##
## LEF for PtnCells ;
## created by Innovus v15.23-s045_1 on Sun Mar  1 18:37:18 2026
##

VERSION 5.8 ;

BUSBITCHARS "[]" ;
DIVIDERCHAR "/" ;

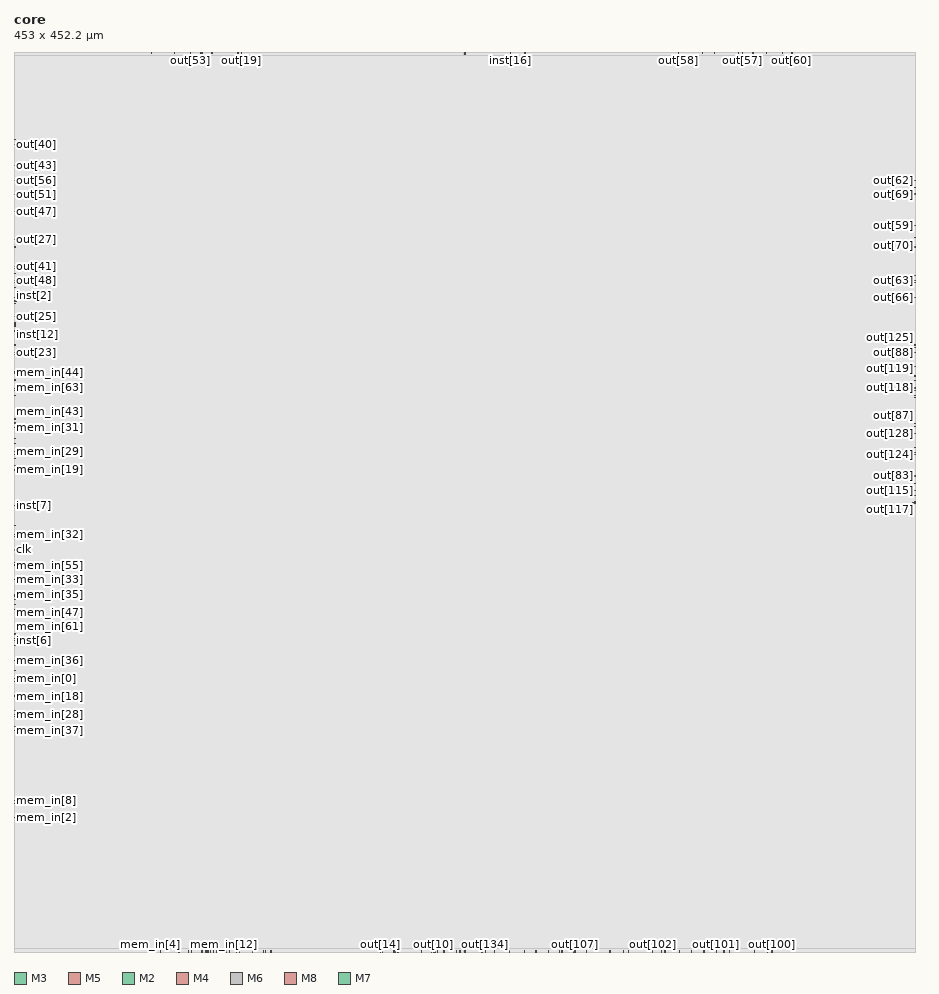
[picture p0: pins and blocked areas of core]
MACRO core
  CLASS BLOCK ;
  SIZE 453.0000 BY 452.2000 ;
  FOREIGN core 0.0000 0.0000 ;
  ORIGIN 0 0 ;
  SYMMETRY X Y R90 ;
  PIN clk
    DIRECTION INPUT ;
    USE SIGNAL ;
    PORT
      LAYER M3 ;
        RECT 0.0000 202.1500 0.5200 202.2500 ;
    END
  END clk
  PIN mem_in[63]
    DIRECTION INPUT ;
    USE SIGNAL ;
    PORT
      LAYER M3 ;
        RECT 0.0000 287.3500 0.5200 287.4500 ;
    END
  END mem_in[63]
  PIN mem_in[62]
    DIRECTION INPUT ;
    USE SIGNAL ;
    PORT
      LAYER M3 ;
        RECT 0.0000 249.9500 0.5200 250.0500 ;
    END
  END mem_in[62]
  PIN mem_in[61]
    DIRECTION INPUT ;
    USE SIGNAL ;
    PORT
      LAYER M3 ;
        RECT 0.0000 159.7500 0.5200 159.8500 ;
    END
  END mem_in[61]
  PIN mem_in[60]
    DIRECTION INPUT ;
    USE SIGNAL ;
    PORT
      LAYER M3 ;
        RECT 0.0000 195.5500 0.5200 195.6500 ;
    END
  END mem_in[60]
  PIN mem_in[59]
    DIRECTION INPUT ;
    USE SIGNAL ;
    PORT
      LAYER M3 ;
        RECT 0.0000 121.1500 0.5200 121.2500 ;
    END
  END mem_in[59]
  PIN mem_in[58]
    DIRECTION INPUT ;
    USE SIGNAL ;
    PORT
      LAYER M3 ;
        RECT 0.0000 141.3500 0.5200 141.4500 ;
    END
  END mem_in[58]
  PIN mem_in[57]
    DIRECTION INPUT ;
    USE SIGNAL ;
    PORT
      LAYER M3 ;
        RECT 0.0000 154.1500 0.5200 154.2500 ;
    END
  END mem_in[57]
  PIN mem_in[56]
    DIRECTION INPUT ;
    USE SIGNAL ;
    PORT
      LAYER M3 ;
        RECT 0.0000 244.3500 0.5200 244.4500 ;
    END
  END mem_in[56]
  PIN mem_in[55]
    DIRECTION INPUT ;
    USE SIGNAL ;
    PORT
      LAYER M3 ;
        RECT 0.0000 194.3500 0.5200 194.4500 ;
    END
  END mem_in[55]
  PIN mem_in[54]
    DIRECTION INPUT ;
    USE SIGNAL ;
    PORT
      LAYER M3 ;
        RECT 0.0000 113.1500 0.5200 113.2500 ;
    END
  END mem_in[54]
  PIN mem_in[53]
    DIRECTION INPUT ;
    USE SIGNAL ;
    PORT
      LAYER M3 ;
        RECT 0.0000 177.1500 0.5200 177.2500 ;
    END
  END mem_in[53]
  PIN mem_in[52]
    DIRECTION INPUT ;
    USE SIGNAL ;
    PORT
      LAYER M3 ;
        RECT 0.0000 178.5500 0.5200 178.6500 ;
    END
  END mem_in[52]
  PIN mem_in[51]
    DIRECTION INPUT ;
    USE SIGNAL ;
    PORT
      LAYER M3 ;
        RECT 0.0000 208.5500 0.5200 208.6500 ;
    END
  END mem_in[51]
  PIN mem_in[50]
    DIRECTION INPUT ;
    USE SIGNAL ;
    PORT
      LAYER M3 ;
        RECT 0.0000 255.5500 0.5200 255.6500 ;
    END
  END mem_in[50]
  PIN mem_in[49]
    DIRECTION INPUT ;
    USE SIGNAL ;
    PORT
      LAYER M3 ;
        RECT 0.0000 283.1500 0.5200 283.2500 ;
    END
  END mem_in[49]
  PIN mem_in[48]
    DIRECTION INPUT ;
    USE SIGNAL ;
    PORT
      LAYER M5 ;
        RECT 0.0000 201.9500 0.5200 202.0500 ;
    END
  END mem_in[48]
  PIN mem_in[47]
    DIRECTION INPUT ;
    USE SIGNAL ;
    PORT
      LAYER M3 ;
        RECT 0.0000 174.7500 0.5200 174.8500 ;
    END
  END mem_in[47]
  PIN mem_in[46]
    DIRECTION INPUT ;
    USE SIGNAL ;
    PORT
      LAYER M3 ;
        RECT 0.0000 214.3500 0.5200 214.4500 ;
    END
  END mem_in[46]
  PIN mem_in[45]
    DIRECTION INPUT ;
    USE SIGNAL ;
    PORT
      LAYER M3 ;
        RECT 0.0000 257.9500 0.5200 258.0500 ;
    END
  END mem_in[45]
  PIN mem_in[44]
    DIRECTION INPUT ;
    USE SIGNAL ;
    PORT
      LAYER M3 ;
        RECT 0.0000 291.3500 0.5200 291.4500 ;
    END
  END mem_in[44]
  PIN mem_in[43]
    DIRECTION INPUT ;
    USE SIGNAL ;
    PORT
      LAYER M3 ;
        RECT 0.0000 267.7500 0.5200 267.8500 ;
    END
  END mem_in[43]
  PIN mem_in[42]
    DIRECTION INPUT ;
    USE SIGNAL ;
    PORT
      LAYER M3 ;
        RECT 0.0000 171.9500 0.5200 172.0500 ;
    END
  END mem_in[42]
  PIN mem_in[41]
    DIRECTION INPUT ;
    USE SIGNAL ;
    PORT
      LAYER M3 ;
        RECT 0.0000 118.3500 0.5200 118.4500 ;
    END
  END mem_in[41]
  PIN mem_in[40]
    DIRECTION INPUT ;
    USE SIGNAL ;
    PORT
      LAYER M2 ;
        RECT 68.8500 0.0000 68.9500 0.5200 ;
    END
  END mem_in[40]
  PIN mem_in[39]
    DIRECTION INPUT ;
    USE SIGNAL ;
    PORT
      LAYER M2 ;
        RECT 125.2500 0.0000 125.3500 0.5200 ;
    END
  END mem_in[39]
  PIN mem_in[38]
    DIRECTION INPUT ;
    USE SIGNAL ;
    PORT
      LAYER M2 ;
        RECT 111.6500 0.0000 111.7500 0.5200 ;
    END
  END mem_in[38]
  PIN mem_in[37]
    DIRECTION INPUT ;
    USE SIGNAL ;
    PORT
      LAYER M3 ;
        RECT 0.0000 111.1500 0.5200 111.2500 ;
    END
  END mem_in[37]
  PIN mem_in[36]
    DIRECTION INPUT ;
    USE SIGNAL ;
    PORT
      LAYER M3 ;
        RECT 0.0000 146.3500 0.5200 146.4500 ;
    END
  END mem_in[36]
  PIN mem_in[35]
    DIRECTION INPUT ;
    USE SIGNAL ;
    PORT
      LAYER M3 ;
        RECT 0.0000 179.3500 0.5200 179.4500 ;
    END
  END mem_in[35]
  PIN mem_in[34]
    DIRECTION INPUT ;
    USE SIGNAL ;
    PORT
      LAYER M3 ;
        RECT 0.0000 265.7500 0.5200 265.8500 ;
    END
  END mem_in[34]
  PIN mem_in[33]
    DIRECTION INPUT ;
    USE SIGNAL ;
    PORT
      LAYER M3 ;
        RECT 0.0000 186.9500 0.5200 187.0500 ;
    END
  END mem_in[33]
  PIN mem_in[32]
    DIRECTION INPUT ;
    USE SIGNAL ;
    PORT
      LAYER M3 ;
        RECT 0.0000 209.5500 0.5200 209.6500 ;
    END
  END mem_in[32]
  PIN mem_in[31]
    DIRECTION INPUT ;
    USE SIGNAL ;
    PORT
      LAYER M3 ;
        RECT 0.0000 263.3500 0.5200 263.4500 ;
    END
  END mem_in[31]
  PIN mem_in[30]
    DIRECTION INPUT ;
    USE SIGNAL ;
    PORT
      LAYER M3 ;
        RECT 0.0000 157.5500 0.5200 157.6500 ;
    END
  END mem_in[30]
  PIN mem_in[29]
    DIRECTION INPUT ;
    USE SIGNAL ;
    PORT
      LAYER M3 ;
        RECT 0.0000 251.3500 0.5200 251.4500 ;
    END
  END mem_in[29]
  PIN mem_in[28]
    DIRECTION INPUT ;
    USE SIGNAL ;
    PORT
      LAYER M3 ;
        RECT 0.0000 119.1500 0.5200 119.2500 ;
    END
  END mem_in[28]
  PIN mem_in[27]
    DIRECTION INPUT ;
    USE SIGNAL ;
    PORT
      LAYER M2 ;
        RECT 119.6500 0.0000 119.7500 0.5200 ;
    END
  END mem_in[27]
  PIN mem_in[26]
    DIRECTION INPUT ;
    USE SIGNAL ;
    PORT
      LAYER M2 ;
        RECT 100.0500 0.0000 100.1500 0.5200 ;
    END
  END mem_in[26]
  PIN mem_in[25]
    DIRECTION INPUT ;
    USE SIGNAL ;
    PORT
      LAYER M2 ;
        RECT 126.2500 0.0000 126.3500 0.5200 ;
    END
  END mem_in[25]
  PIN mem_in[24]
    DIRECTION INPUT ;
    USE SIGNAL ;
    PORT
      LAYER M3 ;
        RECT 0.0000 74.5500 0.5200 74.6500 ;
    END
  END mem_in[24]
  PIN mem_in[23]
    DIRECTION INPUT ;
    USE SIGNAL ;
    PORT
      LAYER M2 ;
        RECT 97.4500 0.0000 97.5500 0.5200 ;
    END
  END mem_in[23]
  PIN mem_in[22]
    DIRECTION INPUT ;
    USE SIGNAL ;
    PORT
      LAYER M2 ;
        RECT 106.4500 0.0000 106.5500 0.5200 ;
    END
  END mem_in[22]
  PIN mem_in[21]
    DIRECTION INPUT ;
    USE SIGNAL ;
    PORT
      LAYER M2 ;
        RECT 82.8500 0.0000 82.9500 0.5200 ;
    END
  END mem_in[21]
  PIN mem_in[20]
    DIRECTION INPUT ;
    USE SIGNAL ;
    PORT
      LAYER M2 ;
        RECT 113.2500 0.0000 113.3500 0.5200 ;
    END
  END mem_in[20]
  PIN mem_in[19]
    DIRECTION INPUT ;
    USE SIGNAL ;
    PORT
      LAYER M3 ;
        RECT 0.0000 242.1500 0.5200 242.2500 ;
    END
  END mem_in[19]
  PIN mem_in[18]
    DIRECTION INPUT ;
    USE SIGNAL ;
    PORT
      LAYER M3 ;
        RECT 0.0000 128.5500 0.5200 128.6500 ;
    END
  END mem_in[18]
  PIN mem_in[17]
    DIRECTION INPUT ;
    USE SIGNAL ;
    PORT
      LAYER M2 ;
        RECT 98.8500 0.0000 98.9500 0.5200 ;
    END
  END mem_in[17]
  PIN mem_in[16]
    DIRECTION INPUT ;
    USE SIGNAL ;
    PORT
      LAYER M2 ;
        RECT 108.0500 0.0000 108.1500 0.5200 ;
    END
  END mem_in[16]
  PIN mem_in[15]
    DIRECTION INPUT ;
    USE SIGNAL ;
    PORT
      LAYER M2 ;
        RECT 73.4500 0.0000 73.5500 0.5200 ;
    END
  END mem_in[15]
  PIN mem_in[14]
    DIRECTION INPUT ;
    USE SIGNAL ;
    PORT
      LAYER M2 ;
        RECT 101.8500 0.0000 101.9500 0.5200 ;
    END
  END mem_in[14]
  PIN mem_in[13]
    DIRECTION INPUT ;
    USE SIGNAL ;
    PORT
      LAYER M2 ;
        RECT 104.6500 0.0000 104.7500 0.5200 ;
    END
  END mem_in[13]
  PIN mem_in[12]
    DIRECTION INPUT ;
    USE SIGNAL ;
    PORT
      LAYER M2 ;
        RECT 105.2500 0.0000 105.3500 0.5200 ;
    END
  END mem_in[12]
  PIN mem_in[11]
    DIRECTION INPUT ;
    USE SIGNAL ;
    PORT
      LAYER M3 ;
        RECT 0.0000 247.9500 0.5200 248.0500 ;
    END
  END mem_in[11]
  PIN mem_in[10]
    DIRECTION INPUT ;
    USE SIGNAL ;
    PORT
      LAYER M3 ;
        RECT 0.0000 135.7500 0.5200 135.8500 ;
    END
  END mem_in[10]
  PIN mem_in[9]
    DIRECTION INPUT ;
    USE SIGNAL ;
    PORT
      LAYER M2 ;
        RECT 129.0500 0.0000 129.1500 0.5200 ;
    END
  END mem_in[9]
  PIN mem_in[8]
    DIRECTION INPUT ;
    USE SIGNAL ;
    PORT
      LAYER M3 ;
        RECT 0.0000 75.9500 0.5200 76.0500 ;
    END
  END mem_in[8]
  PIN mem_in[7]
    DIRECTION INPUT ;
    USE SIGNAL ;
    PORT
      LAYER M2 ;
        RECT 96.4500 0.0000 96.5500 0.5200 ;
    END
  END mem_in[7]
  PIN mem_in[6]
    DIRECTION INPUT ;
    USE SIGNAL ;
    PORT
      LAYER M2 ;
        RECT 87.6500 0.0000 87.7500 0.5200 ;
    END
  END mem_in[6]
  PIN mem_in[5]
    DIRECTION INPUT ;
    USE SIGNAL ;
    PORT
      LAYER M2 ;
        RECT 89.0500 0.0000 89.1500 0.5200 ;
    END
  END mem_in[5]
  PIN mem_in[4]
    DIRECTION INPUT ;
    USE SIGNAL ;
    PORT
      LAYER M2 ;
        RECT 68.4500 0.0000 68.5500 0.5200 ;
    END
  END mem_in[4]
  PIN mem_in[3]
    DIRECTION INPUT ;
    USE SIGNAL ;
    PORT
      LAYER M2 ;
        RECT 94.4500 0.0000 94.5500 0.5200 ;
    END
  END mem_in[3]
  PIN mem_in[2]
    DIRECTION INPUT ;
    USE SIGNAL ;
    PORT
      LAYER M3 ;
        RECT 0.0000 67.3500 0.5200 67.4500 ;
    END
  END mem_in[2]
  PIN mem_in[1]
    DIRECTION INPUT ;
    USE SIGNAL ;
    PORT
      LAYER M4 ;
        RECT 68.8500 0.0000 68.9500 0.5200 ;
    END
  END mem_in[1]
  PIN mem_in[0]
    DIRECTION INPUT ;
    USE SIGNAL ;
    PORT
      LAYER M3 ;
        RECT 0.0000 137.5500 0.5200 137.6500 ;
    END
  END mem_in[0]
  PIN inst[18]
    DIRECTION INPUT ;
    USE SIGNAL ;
    PORT
      LAYER M2 ;
        RECT 226.4500 451.6800 226.5500 452.2000 ;
    END
  END inst[18]
  PIN inst[17]
    DIRECTION INPUT ;
    USE SIGNAL ;
    PORT
      LAYER M4 ;
        RECT 226.4500 451.6800 226.5500 452.2000 ;
    END
  END inst[17]
  PIN inst[16]
    DIRECTION INPUT ;
    USE SIGNAL ;
    PORT
      LAYER M2 ;
        RECT 249.2500 451.6800 249.3500 452.2000 ;
    END
  END inst[16]
  PIN inst[15]
    DIRECTION INPUT ;
    USE SIGNAL ;
    PORT
      LAYER M3 ;
        RECT 0.0000 316.1500 0.5200 316.2500 ;
    END
  END inst[15]
  PIN inst[14]
    DIRECTION INPUT ;
    USE SIGNAL ;
    PORT
      LAYER M3 ;
        RECT 0.0000 314.9500 0.5200 315.0500 ;
    END
  END inst[14]
  PIN inst[13]
    DIRECTION INPUT ;
    USE SIGNAL ;
    PORT
      LAYER M3 ;
        RECT 0.0000 311.9500 0.5200 312.0500 ;
    END
  END inst[13]
  PIN inst[12]
    DIRECTION INPUT ;
    USE SIGNAL ;
    PORT
      LAYER M3 ;
        RECT 0.0000 314.1500 0.5200 314.2500 ;
    END
  END inst[12]
  PIN inst[11]
    DIRECTION INPUT ;
    USE SIGNAL ;
    PORT
      LAYER M6 ;
        RECT 226.4500 451.6800 226.5500 452.2000 ;
    END
  END inst[11]
  PIN inst[10]
    DIRECTION INPUT ;
    USE SIGNAL ;
    PORT
      LAYER M8 ;
        RECT 226.3000 450.7850 226.7000 452.2000 ;
    END
  END inst[10]
  PIN inst[9]
    DIRECTION INPUT ;
    USE SIGNAL ;
    PORT
      LAYER M2 ;
        RECT 226.4500 0.0000 226.5500 0.5200 ;
    END
  END inst[9]
  PIN inst[8]
    DIRECTION INPUT ;
    USE SIGNAL ;
    PORT
      LAYER M4 ;
        RECT 226.4500 0.0000 226.5500 0.5200 ;
    END
  END inst[8]
  PIN inst[7]
    DIRECTION INPUT ;
    USE SIGNAL ;
    PORT
      LAYER M3 ;
        RECT 0.0000 224.1500 0.5200 224.2500 ;
    END
  END inst[7]
  PIN inst[6]
    DIRECTION INPUT ;
    USE SIGNAL ;
    PORT
      LAYER M3 ;
        RECT 0.0000 156.3500 0.5200 156.4500 ;
    END
  END inst[6]
  PIN inst[5]
    DIRECTION INPUT ;
    USE SIGNAL ;
    PORT
      LAYER M3 ;
        RECT 0.0000 326.9500 0.5200 327.0500 ;
    END
  END inst[5]
  PIN inst[4]
    DIRECTION INPUT ;
    USE SIGNAL ;
    PORT
      LAYER M5 ;
        RECT 0.0000 326.9500 0.5200 327.0500 ;
    END
  END inst[4]
  PIN inst[3]
    DIRECTION INPUT ;
    USE SIGNAL ;
    PORT
      LAYER M7 ;
        RECT 0.0000 327.0000 1.4150 327.4000 ;
    END
  END inst[3]
  PIN inst[2]
    DIRECTION INPUT ;
    USE SIGNAL ;
    PORT
      LAYER M3 ;
        RECT 0.0000 325.9500 0.5200 326.0500 ;
    END
  END inst[2]
  PIN inst[1]
    DIRECTION INPUT ;
    USE SIGNAL ;
    PORT
      LAYER M6 ;
        RECT 226.4500 0.0000 226.5500 0.5200 ;
    END
  END inst[1]
  PIN inst[0]
    DIRECTION INPUT ;
    USE SIGNAL ;
    PORT
      LAYER M8 ;
        RECT 226.3000 0.0000 226.7000 1.4150 ;
    END
  END inst[0]
  PIN reset
    DIRECTION INPUT ;
    USE SIGNAL ;
    PORT
      LAYER M2 ;
        RECT 256.6500 451.6800 256.7500 452.2000 ;
    END
  END reset
  PIN out[151]
    DIRECTION OUTPUT ;
    USE SIGNAL ;
    PORT
      LAYER M2 ;
        RECT 256.4500 0.0000 256.5500 0.5200 ;
    END
  END out[151]
  PIN out[150]
    DIRECTION OUTPUT ;
    USE SIGNAL ;
    PORT
      LAYER M2 ;
        RECT 235.0500 0.0000 235.1500 0.5200 ;
    END
  END out[150]
  PIN out[149]
    DIRECTION OUTPUT ;
    USE SIGNAL ;
    PORT
      LAYER M2 ;
        RECT 274.0500 0.0000 274.1500 0.5200 ;
    END
  END out[149]
  PIN out[148]
    DIRECTION OUTPUT ;
    USE SIGNAL ;
    PORT
      LAYER M2 ;
        RECT 299.4500 0.0000 299.5500 0.5200 ;
    END
  END out[148]
  PIN out[147]
    DIRECTION OUTPUT ;
    USE SIGNAL ;
    PORT
      LAYER M2 ;
        RECT 287.4500 0.0000 287.5500 0.5200 ;
    END
  END out[147]
  PIN out[146]
    DIRECTION OUTPUT ;
    USE SIGNAL ;
    PORT
      LAYER M2 ;
        RECT 262.4500 0.0000 262.5500 0.5200 ;
    END
  END out[146]
  PIN out[145]
    DIRECTION OUTPUT ;
    USE SIGNAL ;
    PORT
      LAYER M2 ;
        RECT 281.8500 0.0000 281.9500 0.5200 ;
    END
  END out[145]
  PIN out[144]
    DIRECTION OUTPUT ;
    USE SIGNAL ;
    PORT
      LAYER M2 ;
        RECT 275.2500 0.0000 275.3500 0.5200 ;
    END
  END out[144]
  PIN out[143]
    DIRECTION OUTPUT ;
    USE SIGNAL ;
    PORT
      LAYER M2 ;
        RECT 236.8500 0.0000 236.9500 0.5200 ;
    END
  END out[143]
  PIN out[142]
    DIRECTION OUTPUT ;
    USE SIGNAL ;
    PORT
      LAYER M2 ;
        RECT 261.8500 0.0000 261.9500 0.5200 ;
    END
  END out[142]
  PIN out[141]
    DIRECTION OUTPUT ;
    USE SIGNAL ;
    PORT
      LAYER M2 ;
        RECT 241.4500 0.0000 241.5500 0.5200 ;
    END
  END out[141]
  PIN out[140]
    DIRECTION OUTPUT ;
    USE SIGNAL ;
    PORT
      LAYER M4 ;
        RECT 236.8500 0.0000 236.9500 0.5200 ;
    END
  END out[140]
  PIN out[139]
    DIRECTION OUTPUT ;
    USE SIGNAL ;
    PORT
      LAYER M4 ;
        RECT 262.0500 0.0000 262.1500 0.5200 ;
    END
  END out[139]
  PIN out[138]
    DIRECTION OUTPUT ;
    USE SIGNAL ;
    PORT
      LAYER M2 ;
        RECT 248.8500 0.0000 248.9500 0.5200 ;
    END
  END out[138]
  PIN out[137]
    DIRECTION OUTPUT ;
    USE SIGNAL ;
    PORT
      LAYER M4 ;
        RECT 256.4500 0.0000 256.5500 0.5200 ;
    END
  END out[137]
  PIN out[136]
    DIRECTION OUTPUT ;
    USE SIGNAL ;
    PORT
      LAYER M4 ;
        RECT 262.4500 0.0000 262.5500 0.5200 ;
    END
  END out[136]
  PIN out[135]
    DIRECTION OUTPUT ;
    USE SIGNAL ;
    PORT
      LAYER M4 ;
        RECT 299.4500 0.0000 299.5500 0.5200 ;
    END
  END out[135]
  PIN out[134]
    DIRECTION OUTPUT ;
    USE SIGNAL ;
    PORT
      LAYER M6 ;
        RECT 236.8500 0.0000 236.9500 0.5200 ;
    END
  END out[134]
  PIN out[133]
    DIRECTION OUTPUT ;
    USE SIGNAL ;
    PORT
      LAYER M2 ;
        RECT 268.6500 0.0000 268.7500 0.5200 ;
    END
  END out[133]
  PIN out[132]
    DIRECTION OUTPUT ;
    USE SIGNAL ;
    PORT
      LAYER M3 ;
        RECT 452.4800 250.9500 453.0000 251.0500 ;
    END
  END out[132]
  PIN out[131]
    DIRECTION OUTPUT ;
    USE SIGNAL ;
    PORT
      LAYER M3 ;
        RECT 452.4800 225.7500 453.0000 225.8500 ;
    END
  END out[131]
  PIN out[130]
    DIRECTION OUTPUT ;
    USE SIGNAL ;
    PORT
      LAYER M5 ;
        RECT 452.4800 225.7500 453.0000 225.8500 ;
    END
  END out[130]
  PIN out[129]
    DIRECTION OUTPUT ;
    USE SIGNAL ;
    PORT
      LAYER M3 ;
        RECT 452.4800 229.3500 453.0000 229.4500 ;
    END
  END out[129]
  PIN out[128]
    DIRECTION OUTPUT ;
    USE SIGNAL ;
    PORT
      LAYER M3 ;
        RECT 452.4800 260.5500 453.0000 260.6500 ;
    END
  END out[128]
  PIN out[127]
    DIRECTION OUTPUT ;
    USE SIGNAL ;
    PORT
      LAYER M7 ;
        RECT 451.5850 225.4000 453.0000 225.8000 ;
    END
  END out[127]
  PIN out[126]
    DIRECTION OUTPUT ;
    USE SIGNAL ;
    PORT
      LAYER M3 ;
        RECT 452.4800 264.1500 453.0000 264.2500 ;
    END
  END out[126]
  PIN out[125]
    DIRECTION OUTPUT ;
    USE SIGNAL ;
    PORT
      LAYER M3 ;
        RECT 452.4800 304.9500 453.0000 305.0500 ;
    END
  END out[125]
  PIN out[124]
    DIRECTION OUTPUT ;
    USE SIGNAL ;
    PORT
      LAYER M3 ;
        RECT 452.4800 249.7500 453.0000 249.8500 ;
    END
  END out[124]
  PIN out[123]
    DIRECTION OUTPUT ;
    USE SIGNAL ;
    PORT
      LAYER M3 ;
        RECT 452.4800 294.1500 453.0000 294.2500 ;
    END
  END out[123]
  PIN out[122]
    DIRECTION OUTPUT ;
    USE SIGNAL ;
    PORT
      LAYER M3 ;
        RECT 452.4800 282.1500 453.0000 282.2500 ;
    END
  END out[122]
  PIN out[121]
    DIRECTION OUTPUT ;
    USE SIGNAL ;
    PORT
      LAYER M5 ;
        RECT 452.4800 282.1500 453.0000 282.2500 ;
    END
  END out[121]
  PIN out[120]
    DIRECTION OUTPUT ;
    USE SIGNAL ;
    PORT
      LAYER M3 ;
        RECT 452.4800 225.3500 453.0000 225.4500 ;
    END
  END out[120]
  PIN out[119]
    DIRECTION OUTPUT ;
    USE SIGNAL ;
    PORT
      LAYER M3 ;
        RECT 452.4800 289.3500 453.0000 289.4500 ;
    END
  END out[119]
  PIN out[118]
    DIRECTION OUTPUT ;
    USE SIGNAL ;
    PORT
      LAYER M3 ;
        RECT 452.4800 283.3500 453.0000 283.4500 ;
    END
  END out[118]
  PIN out[117]
    DIRECTION OUTPUT ;
    USE SIGNAL ;
    PORT
      LAYER M3 ;
        RECT 452.4800 226.1500 453.0000 226.2500 ;
    END
  END out[117]
  PIN out[116]
    DIRECTION OUTPUT ;
    USE SIGNAL ;
    PORT
      LAYER M5 ;
        RECT 452.4800 229.3500 453.0000 229.4500 ;
    END
  END out[116]
  PIN out[115]
    DIRECTION OUTPUT ;
    USE SIGNAL ;
    PORT
      LAYER M3 ;
        RECT 452.4800 231.7500 453.0000 231.8500 ;
    END
  END out[115]
  PIN out[114]
    DIRECTION OUTPUT ;
    USE SIGNAL ;
    PORT
      LAYER M3 ;
        RECT 452.4800 303.7500 453.0000 303.8500 ;
    END
  END out[114]
  PIN out[113]
    DIRECTION OUTPUT ;
    USE SIGNAL ;
    PORT
      LAYER M2 ;
        RECT 378.4500 0.0000 378.5500 0.5200 ;
    END
  END out[113]
  PIN out[112]
    DIRECTION OUTPUT ;
    USE SIGNAL ;
    PORT
      LAYER M2 ;
        RECT 325.4500 0.0000 325.5500 0.5200 ;
    END
  END out[112]
  PIN out[111]
    DIRECTION OUTPUT ;
    USE SIGNAL ;
    PORT
      LAYER M2 ;
        RECT 306.0500 0.0000 306.1500 0.5200 ;
    END
  END out[111]
  PIN out[110]
    DIRECTION OUTPUT ;
    USE SIGNAL ;
    PORT
      LAYER M2 ;
        RECT 327.0500 0.0000 327.1500 0.5200 ;
    END
  END out[110]
  PIN out[109]
    DIRECTION OUTPUT ;
    USE SIGNAL ;
    PORT
      LAYER M2 ;
        RECT 340.4500 0.0000 340.5500 0.5200 ;
    END
  END out[109]
  PIN out[108]
    DIRECTION OUTPUT ;
    USE SIGNAL ;
    PORT
      LAYER M6 ;
        RECT 299.4500 0.0000 299.5500 0.5200 ;
    END
  END out[108]
  PIN out[107]
    DIRECTION OUTPUT ;
    USE SIGNAL ;
    PORT
      LAYER M4 ;
        RECT 281.8500 0.0000 281.9500 0.5200 ;
    END
  END out[107]
  PIN out[106]
    DIRECTION OUTPUT ;
    USE SIGNAL ;
    PORT
      LAYER M2 ;
        RECT 359.4500 0.0000 359.5500 0.5200 ;
    END
  END out[106]
  PIN out[105]
    DIRECTION OUTPUT ;
    USE SIGNAL ;
    PORT
      LAYER M2 ;
        RECT 281.2500 0.0000 281.3500 0.5200 ;
    END
  END out[105]
  PIN out[104]
    DIRECTION OUTPUT ;
    USE SIGNAL ;
    PORT
      LAYER M4 ;
        RECT 327.2500 0.0000 327.3500 0.5200 ;
    END
  END out[104]
  PIN out[103]
    DIRECTION OUTPUT ;
    USE SIGNAL ;
    PORT
      LAYER M2 ;
        RECT 356.6500 0.0000 356.7500 0.5200 ;
    END
  END out[103]
  PIN out[102]
    DIRECTION OUTPUT ;
    USE SIGNAL ;
    PORT
      LAYER M2 ;
        RECT 320.8500 0.0000 320.9500 0.5200 ;
    END
  END out[102]
  PIN out[101]
    DIRECTION OUTPUT ;
    USE SIGNAL ;
    PORT
      LAYER M2 ;
        RECT 352.8500 0.0000 352.9500 0.5200 ;
    END
  END out[101]
  PIN out[100]
    DIRECTION OUTPUT ;
    USE SIGNAL ;
    PORT
      LAYER M2 ;
        RECT 380.8500 0.0000 380.9500 0.5200 ;
    END
  END out[100]
  PIN out[99]
    DIRECTION OUTPUT ;
    USE SIGNAL ;
    PORT
      LAYER M2 ;
        RECT 372.0500 0.0000 372.1500 0.5200 ;
    END
  END out[99]
  PIN out[98]
    DIRECTION OUTPUT ;
    USE SIGNAL ;
    PORT
      LAYER M4 ;
        RECT 306.0500 0.0000 306.1500 0.5200 ;
    END
  END out[98]
  PIN out[97]
    DIRECTION OUTPUT ;
    USE SIGNAL ;
    PORT
      LAYER M2 ;
        RECT 334.2500 0.0000 334.3500 0.5200 ;
    END
  END out[97]
  PIN out[96]
    DIRECTION OUTPUT ;
    USE SIGNAL ;
    PORT
      LAYER M2 ;
        RECT 308.8500 0.0000 308.9500 0.5200 ;
    END
  END out[96]
  PIN out[95]
    DIRECTION OUTPUT ;
    USE SIGNAL ;
    PORT
      LAYER M2 ;
        RECT 346.6500 0.0000 346.7500 0.5200 ;
    END
  END out[95]
  PIN out[94]
    DIRECTION OUTPUT ;
    USE SIGNAL ;
    PORT
      LAYER M3 ;
        RECT 452.4800 339.7500 453.0000 339.8500 ;
    END
  END out[94]
  PIN out[93]
    DIRECTION OUTPUT ;
    USE SIGNAL ;
    PORT
      LAYER M3 ;
        RECT 452.4800 238.9500 453.0000 239.0500 ;
    END
  END out[93]
  PIN out[92]
    DIRECTION OUTPUT ;
    USE SIGNAL ;
    PORT
      LAYER M3 ;
        RECT 452.4800 354.1500 453.0000 354.2500 ;
    END
  END out[92]
  PIN out[91]
    DIRECTION OUTPUT ;
    USE SIGNAL ;
    PORT
      LAYER M3 ;
        RECT 452.4800 278.5500 453.0000 278.6500 ;
    END
  END out[91]
  PIN out[90]
    DIRECTION OUTPUT ;
    USE SIGNAL ;
    PORT
      LAYER M3 ;
        RECT 452.4800 279.7500 453.0000 279.8500 ;
    END
  END out[90]
  PIN out[89]
    DIRECTION OUTPUT ;
    USE SIGNAL ;
    PORT
      LAYER M3 ;
        RECT 452.4800 301.3500 453.0000 301.4500 ;
    END
  END out[89]
  PIN out[88]
    DIRECTION OUTPUT ;
    USE SIGNAL ;
    PORT
      LAYER M5 ;
        RECT 452.4800 301.3500 453.0000 301.4500 ;
    END
  END out[88]
  PIN out[87]
    DIRECTION OUTPUT ;
    USE SIGNAL ;
    PORT
      LAYER M3 ;
        RECT 452.4800 265.3500 453.0000 265.4500 ;
    END
  END out[87]
  PIN out[86]
    DIRECTION OUTPUT ;
    USE SIGNAL ;
    PORT
      LAYER M5 ;
        RECT 452.4800 279.7500 453.0000 279.8500 ;
    END
  END out[86]
  PIN out[85]
    DIRECTION OUTPUT ;
    USE SIGNAL ;
    PORT
      LAYER M3 ;
        RECT 452.4800 286.9500 453.0000 287.0500 ;
    END
  END out[85]
  PIN out[84]
    DIRECTION OUTPUT ;
    USE SIGNAL ;
    PORT
      LAYER M3 ;
        RECT 452.4800 337.3500 453.0000 337.4500 ;
    END
  END out[84]
  PIN out[83]
    DIRECTION OUTPUT ;
    USE SIGNAL ;
    PORT
      LAYER M3 ;
        RECT 452.4800 235.3500 453.0000 235.4500 ;
    END
  END out[83]
  PIN out[82]
    DIRECTION OUTPUT ;
    USE SIGNAL ;
    PORT
      LAYER M5 ;
        RECT 452.4800 238.9500 453.0000 239.0500 ;
    END
  END out[82]
  PIN out[81]
    DIRECTION OUTPUT ;
    USE SIGNAL ;
    PORT
      LAYER M5 ;
        RECT 452.4800 289.3500 453.0000 289.4500 ;
    END
  END out[81]
  PIN out[80]
    DIRECTION OUTPUT ;
    USE SIGNAL ;
    PORT
      LAYER M3 ;
        RECT 452.4800 336.1500 453.0000 336.2500 ;
    END
  END out[80]
  PIN out[79]
    DIRECTION OUTPUT ;
    USE SIGNAL ;
    PORT
      LAYER M7 ;
        RECT 451.5850 239.0000 453.0000 239.4000 ;
    END
  END out[79]
  PIN out[78]
    DIRECTION OUTPUT ;
    USE SIGNAL ;
    PORT
      LAYER M5 ;
        RECT 452.4800 286.9500 453.0000 287.0500 ;
    END
  END out[78]
  PIN out[77]
    DIRECTION OUTPUT ;
    USE SIGNAL ;
    PORT
      LAYER M3 ;
        RECT 452.4800 253.3500 453.0000 253.4500 ;
    END
  END out[77]
  PIN out[76]
    DIRECTION OUTPUT ;
    USE SIGNAL ;
    PORT
      LAYER M3 ;
        RECT 452.4800 328.9500 453.0000 329.0500 ;
    END
  END out[76]
  PIN out[75]
    DIRECTION OUTPUT ;
    USE SIGNAL ;
    PORT
      LAYER M2 ;
        RECT 363.8500 451.6800 363.9500 452.2000 ;
    END
  END out[75]
  PIN out[74]
    DIRECTION OUTPUT ;
    USE SIGNAL ;
    PORT
      LAYER M3 ;
        RECT 452.4800 384.1500 453.0000 384.2500 ;
    END
  END out[74]
  PIN out[73]
    DIRECTION OUTPUT ;
    USE SIGNAL ;
    PORT
      LAYER M3 ;
        RECT 452.4800 380.5500 453.0000 380.6500 ;
    END
  END out[73]
  PIN out[72]
    DIRECTION OUTPUT ;
    USE SIGNAL ;
    PORT
      LAYER M2 ;
        RECT 371.2500 451.6800 371.3500 452.2000 ;
    END
  END out[72]
  PIN out[71]
    DIRECTION OUTPUT ;
    USE SIGNAL ;
    PORT
      LAYER M2 ;
        RECT 352.0500 451.6800 352.1500 452.2000 ;
    END
  END out[71]
  PIN out[70]
    DIRECTION OUTPUT ;
    USE SIGNAL ;
    PORT
      LAYER M3 ;
        RECT 452.4800 358.9500 453.0000 359.0500 ;
    END
  END out[70]
  PIN out[69]
    DIRECTION OUTPUT ;
    USE SIGNAL ;
    PORT
      LAYER M5 ;
        RECT 452.4800 380.5500 453.0000 380.6500 ;
    END
  END out[69]
  PIN out[68]
    DIRECTION OUTPUT ;
    USE SIGNAL ;
    PORT
      LAYER M2 ;
        RECT 346.0500 451.6800 346.1500 452.2000 ;
    END
  END out[68]
  PIN out[67]
    DIRECTION OUTPUT ;
    USE SIGNAL ;
    PORT
      LAYER M2 ;
        RECT 386.0500 451.6800 386.1500 452.2000 ;
    END
  END out[67]
  PIN out[66]
    DIRECTION OUTPUT ;
    USE SIGNAL ;
    PORT
      LAYER M5 ;
        RECT 452.4800 328.9500 453.0000 329.0500 ;
    END
  END out[66]
  PIN out[65]
    DIRECTION OUTPUT ;
    USE SIGNAL ;
    PORT
      LAYER M7 ;
        RECT 451.5850 328.6000 453.0000 329.0000 ;
    END
  END out[65]
  PIN out[64]
    DIRECTION OUTPUT ;
    USE SIGNAL ;
    PORT
      LAYER M7 ;
        RECT 451.5850 380.6000 453.0000 381.0000 ;
    END
  END out[64]
  PIN out[63]
    DIRECTION OUTPUT ;
    USE SIGNAL ;
    PORT
      LAYER M5 ;
        RECT 452.4800 337.3500 453.0000 337.4500 ;
    END
  END out[63]
  PIN out[62]
    DIRECTION OUTPUT ;
    USE SIGNAL ;
    PORT
      LAYER M3 ;
        RECT 452.4800 387.7500 453.0000 387.8500 ;
    END
  END out[62]
  PIN out[61]
    DIRECTION OUTPUT ;
    USE SIGNAL ;
    PORT
      LAYER M2 ;
        RECT 377.8500 451.6800 377.9500 452.2000 ;
    END
  END out[61]
  PIN out[60]
    DIRECTION OUTPUT ;
    USE SIGNAL ;
    PORT
      LAYER M2 ;
        RECT 390.8500 451.6800 390.9500 452.2000 ;
    END
  END out[60]
  PIN out[59]
    DIRECTION OUTPUT ;
    USE SIGNAL ;
    PORT
      LAYER M3 ;
        RECT 452.4800 364.9500 453.0000 365.0500 ;
    END
  END out[59]
  PIN out[58]
    DIRECTION OUTPUT ;
    USE SIGNAL ;
    PORT
      LAYER M2 ;
        RECT 333.6500 451.6800 333.7500 452.2000 ;
    END
  END out[58]
  PIN out[57]
    DIRECTION OUTPUT ;
    USE SIGNAL ;
    PORT
      LAYER M2 ;
        RECT 365.8500 451.6800 365.9500 452.2000 ;
    END
  END out[57]
  PIN out[56]
    DIRECTION OUTPUT ;
    USE SIGNAL ;
    PORT
      LAYER M3 ;
        RECT 0.0000 387.7500 0.5200 387.8500 ;
    END
  END out[56]
  PIN out[55]
    DIRECTION OUTPUT ;
    USE SIGNAL ;
    PORT
      LAYER M2 ;
        RECT 94.4500 451.6800 94.5500 452.2000 ;
    END
  END out[55]
  PIN out[54]
    DIRECTION OUTPUT ;
    USE SIGNAL ;
    PORT
      LAYER M2 ;
        RECT 80.6500 451.6800 80.7500 452.2000 ;
    END
  END out[54]
  PIN out[53]
    DIRECTION OUTPUT ;
    USE SIGNAL ;
    PORT
      LAYER M2 ;
        RECT 88.4500 451.6800 88.5500 452.2000 ;
    END
  END out[53]
  PIN out[52]
    DIRECTION OUTPUT ;
    USE SIGNAL ;
    PORT
      LAYER M3 ;
        RECT 0.0000 340.9500 0.5200 341.0500 ;
    END
  END out[52]
  PIN out[51]
    DIRECTION OUTPUT ;
    USE SIGNAL ;
    PORT
      LAYER M3 ;
        RECT 0.0000 380.5500 0.5200 380.6500 ;
    END
  END out[51]
  PIN out[50]
    DIRECTION OUTPUT ;
    USE SIGNAL ;
    PORT
      LAYER M3 ;
        RECT 0.0000 405.7500 0.5200 405.8500 ;
    END
  END out[50]
  PIN out[49]
    DIRECTION OUTPUT ;
    USE SIGNAL ;
    PORT
      LAYER M3 ;
        RECT 0.0000 408.1500 0.5200 408.2500 ;
    END
  END out[49]
  PIN out[48]
    DIRECTION OUTPUT ;
    USE SIGNAL ;
    PORT
      LAYER M3 ;
        RECT 0.0000 337.3500 0.5200 337.4500 ;
    END
  END out[48]
  PIN out[47]
    DIRECTION OUTPUT ;
    USE SIGNAL ;
    PORT
      LAYER M3 ;
        RECT 0.0000 372.1500 0.5200 372.2500 ;
    END
  END out[47]
  PIN out[46]
    DIRECTION OUTPUT ;
    USE SIGNAL ;
    PORT
      LAYER M3 ;
        RECT 0.0000 336.1500 0.5200 336.2500 ;
    END
  END out[46]
  PIN out[45]
    DIRECTION OUTPUT ;
    USE SIGNAL ;
    PORT
      LAYER M3 ;
        RECT 0.0000 343.3500 0.5200 343.4500 ;
    END
  END out[45]
  PIN out[44]
    DIRECTION OUTPUT ;
    USE SIGNAL ;
    PORT
      LAYER M5 ;
        RECT 0.0000 336.1500 0.5200 336.2500 ;
    END
  END out[44]
  PIN out[43]
    DIRECTION OUTPUT ;
    USE SIGNAL ;
    PORT
      LAYER M3 ;
        RECT 0.0000 394.9500 0.5200 395.0500 ;
    END
  END out[43]
  PIN out[42]
    DIRECTION OUTPUT ;
    USE SIGNAL ;
    PORT
      LAYER M3 ;
        RECT 0.0000 354.1500 0.5200 354.2500 ;
    END
  END out[42]
  PIN out[41]
    DIRECTION OUTPUT ;
    USE SIGNAL ;
    PORT
      LAYER M3 ;
        RECT 0.0000 344.5500 0.5200 344.6500 ;
    END
  END out[41]
  PIN out[40]
    DIRECTION OUTPUT ;
    USE SIGNAL ;
    PORT
      LAYER M5 ;
        RECT 0.0000 405.7500 0.5200 405.8500 ;
    END
  END out[40]
  PIN out[39]
    DIRECTION OUTPUT ;
    USE SIGNAL ;
    PORT
      LAYER M2 ;
        RECT 69.0500 451.6800 69.1500 452.2000 ;
    END
  END out[39]
  PIN out[38]
    DIRECTION OUTPUT ;
    USE SIGNAL ;
    PORT
      LAYER M4 ;
        RECT 94.6500 451.6800 94.7500 452.2000 ;
    END
  END out[38]
  PIN out[37]
    DIRECTION OUTPUT ;
    USE SIGNAL ;
    PORT
      LAYER M2 ;
        RECT 99.4500 451.6800 99.5500 452.2000 ;
    END
  END out[37]
  PIN out[36]
    DIRECTION OUTPUT ;
    USE SIGNAL ;
    PORT
      LAYER M3 ;
        RECT 0.0000 328.9500 0.5200 329.0500 ;
    END
  END out[36]
  PIN out[35]
    DIRECTION OUTPUT ;
    USE SIGNAL ;
    PORT
      LAYER M3 ;
        RECT 0.0000 304.9500 0.5200 305.0500 ;
    END
  END out[35]
  PIN out[34]
    DIRECTION OUTPUT ;
    USE SIGNAL ;
    PORT
      LAYER M3 ;
        RECT 0.0000 279.7500 0.5200 279.8500 ;
    END
  END out[34]
  PIN out[33]
    DIRECTION OUTPUT ;
    USE SIGNAL ;
    PORT
      LAYER M3 ;
        RECT 0.0000 290.5500 0.5200 290.6500 ;
    END
  END out[33]
  PIN out[32]
    DIRECTION OUTPUT ;
    USE SIGNAL ;
    PORT
      LAYER M3 ;
        RECT 0.0000 282.1500 0.5200 282.2500 ;
    END
  END out[32]
  PIN out[31]
    DIRECTION OUTPUT ;
    USE SIGNAL ;
    PORT
      LAYER M3 ;
        RECT 0.0000 300.1500 0.5200 300.2500 ;
    END
  END out[31]
  PIN out[30]
    DIRECTION OUTPUT ;
    USE SIGNAL ;
    PORT
      LAYER M3 ;
        RECT 0.0000 333.7500 0.5200 333.8500 ;
    END
  END out[30]
  PIN out[29]
    DIRECTION OUTPUT ;
    USE SIGNAL ;
    PORT
      LAYER M3 ;
        RECT 0.0000 301.3500 0.5200 301.4500 ;
    END
  END out[29]
  PIN out[28]
    DIRECTION OUTPUT ;
    USE SIGNAL ;
    PORT
      LAYER M2 ;
        RECT 112.4500 451.6800 112.5500 452.2000 ;
    END
  END out[28]
  PIN out[27]
    DIRECTION OUTPUT ;
    USE SIGNAL ;
    PORT
      LAYER M3 ;
        RECT 0.0000 357.7500 0.5200 357.8500 ;
    END
  END out[27]
  PIN out[26]
    DIRECTION OUTPUT ;
    USE SIGNAL ;
    PORT
      LAYER M5 ;
        RECT 0.0000 312.1500 0.5200 312.2500 ;
    END
  END out[26]
  PIN out[25]
    DIRECTION OUTPUT ;
    USE SIGNAL ;
    PORT
      LAYER M3 ;
        RECT 0.0000 319.3500 0.5200 319.4500 ;
    END
  END out[25]
  PIN out[24]
    DIRECTION OUTPUT ;
    USE SIGNAL ;
    PORT
      LAYER M5 ;
        RECT 0.0000 328.9500 0.5200 329.0500 ;
    END
  END out[24]
  PIN out[23]
    DIRECTION OUTPUT ;
    USE SIGNAL ;
    PORT
      LAYER M5 ;
        RECT 0.0000 301.3500 0.5200 301.4500 ;
    END
  END out[23]
  PIN out[22]
    DIRECTION OUTPUT ;
    USE SIGNAL ;
    PORT
      LAYER M5 ;
        RECT 0.0000 340.9500 0.5200 341.0500 ;
    END
  END out[22]
  PIN out[21]
    DIRECTION OUTPUT ;
    USE SIGNAL ;
    PORT
      LAYER M3 ;
        RECT 0.0000 315.7500 0.5200 315.8500 ;
    END
  END out[21]
  PIN out[20]
    DIRECTION OUTPUT ;
    USE SIGNAL ;
    PORT
      LAYER M2 ;
        RECT 93.8500 451.6800 93.9500 452.2000 ;
    END
  END out[20]
  PIN out[19]
    DIRECTION OUTPUT ;
    USE SIGNAL ;
    PORT
      LAYER M2 ;
        RECT 114.2500 451.6800 114.3500 452.2000 ;
    END
  END out[19]
  PIN out[18]
    DIRECTION OUTPUT ;
    USE SIGNAL ;
    PORT
      LAYER M2 ;
        RECT 211.4500 0.0000 211.5500 0.5200 ;
    END
  END out[18]
  PIN out[17]
    DIRECTION OUTPUT ;
    USE SIGNAL ;
    PORT
      LAYER M2 ;
        RECT 224.0500 0.0000 224.1500 0.5200 ;
    END
  END out[17]
  PIN out[16]
    DIRECTION OUTPUT ;
    USE SIGNAL ;
    PORT
      LAYER M2 ;
        RECT 215.8500 0.0000 215.9500 0.5200 ;
    END
  END out[16]
  PIN out[15]
    DIRECTION OUTPUT ;
    USE SIGNAL ;
    PORT
      LAYER M2 ;
        RECT 190.8500 0.0000 190.9500 0.5200 ;
    END
  END out[15]
  PIN out[14]
    DIRECTION OUTPUT ;
    USE SIGNAL ;
    PORT
      LAYER M2 ;
        RECT 184.2500 0.0000 184.3500 0.5200 ;
    END
  END out[14]
  PIN out[13]
    DIRECTION OUTPUT ;
    USE SIGNAL ;
    PORT
      LAYER M2 ;
        RECT 222.2500 0.0000 222.3500 0.5200 ;
    END
  END out[13]
  PIN out[12]
    DIRECTION OUTPUT ;
    USE SIGNAL ;
    PORT
      LAYER M4 ;
        RECT 215.8500 0.0000 215.9500 0.5200 ;
    END
  END out[12]
  PIN out[11]
    DIRECTION OUTPUT ;
    USE SIGNAL ;
    PORT
      LAYER M2 ;
        RECT 209.6500 0.0000 209.7500 0.5200 ;
    END
  END out[11]
  PIN out[10]
    DIRECTION OUTPUT ;
    USE SIGNAL ;
    PORT
      LAYER M2 ;
        RECT 210.6500 0.0000 210.7500 0.5200 ;
    END
  END out[10]
  PIN out[9]
    DIRECTION OUTPUT ;
    USE SIGNAL ;
    PORT
      LAYER M4 ;
        RECT 190.8500 0.0000 190.9500 0.5200 ;
    END
  END out[9]
  PIN out[8]
    DIRECTION OUTPUT ;
    USE SIGNAL ;
    PORT
      LAYER M2 ;
        RECT 212.6500 0.0000 212.7500 0.5200 ;
    END
  END out[8]
  PIN out[7]
    DIRECTION OUTPUT ;
    USE SIGNAL ;
    PORT
      LAYER M2 ;
        RECT 204.8500 0.0000 204.9500 0.5200 ;
    END
  END out[7]
  PIN out[6]
    DIRECTION OUTPUT ;
    USE SIGNAL ;
    PORT
      LAYER M2 ;
        RECT 192.8500 0.0000 192.9500 0.5200 ;
    END
  END out[6]
  PIN out[5]
    DIRECTION OUTPUT ;
    USE SIGNAL ;
    PORT
      LAYER M2 ;
        RECT 185.0500 0.0000 185.1500 0.5200 ;
    END
  END out[5]
  PIN out[4]
    DIRECTION OUTPUT ;
    USE SIGNAL ;
    PORT
      LAYER M2 ;
        RECT 211.8500 0.0000 211.9500 0.5200 ;
    END
  END out[4]
  PIN out[3]
    DIRECTION OUTPUT ;
    USE SIGNAL ;
    PORT
      LAYER M4 ;
        RECT 210.8500 0.0000 210.9500 0.5200 ;
    END
  END out[3]
  PIN out[2]
    DIRECTION OUTPUT ;
    USE SIGNAL ;
    PORT
      LAYER M2 ;
        RECT 216.2500 0.0000 216.3500 0.5200 ;
    END
  END out[2]
  PIN out[1]
    DIRECTION OUTPUT ;
    USE SIGNAL ;
    PORT
      LAYER M4 ;
        RECT 223.8500 0.0000 223.9500 0.5200 ;
    END
  END out[1]
  PIN out[0]
    DIRECTION OUTPUT ;
    USE SIGNAL ;
    PORT
      LAYER M2 ;
        RECT 191.4500 0.0000 191.5500 0.5200 ;
    END
  END out[0]
  OBS
    LAYER M1 ;
      RECT 0.0000 0.0000 453.0000 452.2000 ;
    LAYER M2 ;
      RECT 391.0500 451.5800 453.0000 452.2000 ;
      RECT 386.2500 451.5800 390.7500 452.2000 ;
      RECT 378.0500 451.5800 385.9500 452.2000 ;
      RECT 371.4500 451.5800 377.7500 452.2000 ;
      RECT 366.0500 451.5800 371.1500 452.2000 ;
      RECT 364.0500 451.5800 365.7500 452.2000 ;
      RECT 352.2500 451.5800 363.7500 452.2000 ;
      RECT 346.2500 451.5800 351.9500 452.2000 ;
      RECT 333.8500 451.5800 345.9500 452.2000 ;
      RECT 256.8500 451.5800 333.5500 452.2000 ;
      RECT 249.4500 451.5800 256.5500 452.2000 ;
      RECT 226.6500 451.5800 249.1500 452.2000 ;
      RECT 114.4500 451.5800 226.3500 452.2000 ;
      RECT 112.6500 451.5800 114.1500 452.2000 ;
      RECT 99.6500 451.5800 112.3500 452.2000 ;
      RECT 94.6500 451.5800 99.3500 452.2000 ;
      RECT 94.0500 451.5800 94.3500 452.2000 ;
      RECT 88.6500 451.5800 93.7500 452.2000 ;
      RECT 80.8500 451.5800 88.3500 452.2000 ;
      RECT 69.2500 451.5800 80.5500 452.2000 ;
      RECT 0.0000 451.5800 68.9500 452.2000 ;
      RECT 0.0000 0.6200 453.0000 451.5800 ;
      RECT 381.0500 0.0000 453.0000 0.6200 ;
      RECT 378.6500 0.0000 380.7500 0.6200 ;
      RECT 372.2500 0.0000 378.3500 0.6200 ;
      RECT 359.6500 0.0000 371.9500 0.6200 ;
      RECT 356.8500 0.0000 359.3500 0.6200 ;
      RECT 353.0500 0.0000 356.5500 0.6200 ;
      RECT 346.8500 0.0000 352.7500 0.6200 ;
      RECT 340.6500 0.0000 346.5500 0.6200 ;
      RECT 334.4500 0.0000 340.3500 0.6200 ;
      RECT 327.2500 0.0000 334.1500 0.6200 ;
      RECT 325.6500 0.0000 326.9500 0.6200 ;
      RECT 321.0500 0.0000 325.3500 0.6200 ;
      RECT 309.0500 0.0000 320.7500 0.6200 ;
      RECT 306.2500 0.0000 308.7500 0.6200 ;
      RECT 299.6500 0.0000 305.9500 0.6200 ;
      RECT 287.6500 0.0000 299.3500 0.6200 ;
      RECT 282.0500 0.0000 287.3500 0.6200 ;
      RECT 281.4500 0.0000 281.7500 0.6200 ;
      RECT 275.4500 0.0000 281.1500 0.6200 ;
      RECT 274.2500 0.0000 275.1500 0.6200 ;
      RECT 268.8500 0.0000 273.9500 0.6200 ;
      RECT 262.6500 0.0000 268.5500 0.6200 ;
      RECT 262.0500 0.0000 262.3500 0.6200 ;
      RECT 256.6500 0.0000 261.7500 0.6200 ;
      RECT 249.0500 0.0000 256.3500 0.6200 ;
      RECT 241.6500 0.0000 248.7500 0.6200 ;
      RECT 237.0500 0.0000 241.3500 0.6200 ;
      RECT 235.2500 0.0000 236.7500 0.6200 ;
      RECT 226.6500 0.0000 234.9500 0.6200 ;
      RECT 224.2500 0.0000 226.3500 0.6200 ;
      RECT 222.4500 0.0000 223.9500 0.6200 ;
      RECT 216.4500 0.0000 222.1500 0.6200 ;
      RECT 216.0500 0.0000 216.1500 0.6200 ;
      RECT 212.8500 0.0000 215.7500 0.6200 ;
      RECT 212.0500 0.0000 212.5500 0.6200 ;
      RECT 211.6500 0.0000 211.7500 0.6200 ;
      RECT 210.8500 0.0000 211.3500 0.6200 ;
      RECT 209.8500 0.0000 210.5500 0.6200 ;
      RECT 205.0500 0.0000 209.5500 0.6200 ;
      RECT 193.0500 0.0000 204.7500 0.6200 ;
      RECT 191.6500 0.0000 192.7500 0.6200 ;
      RECT 191.0500 0.0000 191.3500 0.6200 ;
      RECT 185.2500 0.0000 190.7500 0.6200 ;
      RECT 184.4500 0.0000 184.9500 0.6200 ;
      RECT 129.2500 0.0000 184.1500 0.6200 ;
      RECT 126.4500 0.0000 128.9500 0.6200 ;
      RECT 125.4500 0.0000 126.1500 0.6200 ;
      RECT 119.8500 0.0000 125.1500 0.6200 ;
      RECT 113.4500 0.0000 119.5500 0.6200 ;
      RECT 111.8500 0.0000 113.1500 0.6200 ;
      RECT 108.2500 0.0000 111.5500 0.6200 ;
      RECT 106.6500 0.0000 107.9500 0.6200 ;
      RECT 105.4500 0.0000 106.3500 0.6200 ;
      RECT 104.8500 0.0000 105.1500 0.6200 ;
      RECT 102.0500 0.0000 104.5500 0.6200 ;
      RECT 100.2500 0.0000 101.7500 0.6200 ;
      RECT 99.0500 0.0000 99.9500 0.6200 ;
      RECT 97.6500 0.0000 98.7500 0.6200 ;
      RECT 96.6500 0.0000 97.3500 0.6200 ;
      RECT 94.6500 0.0000 96.3500 0.6200 ;
      RECT 89.2500 0.0000 94.3500 0.6200 ;
      RECT 87.8500 0.0000 88.9500 0.6200 ;
      RECT 83.0500 0.0000 87.5500 0.6200 ;
      RECT 73.6500 0.0000 82.7500 0.6200 ;
      RECT 69.0500 0.0000 73.3500 0.6200 ;
      RECT 68.6500 0.0000 68.7500 0.6200 ;
      RECT 0.0000 0.0000 68.3500 0.6200 ;
    LAYER M3 ;
      RECT 0.0000 408.3500 453.0000 452.2000 ;
      RECT 0.6200 408.0500 453.0000 408.3500 ;
      RECT 0.0000 405.9500 453.0000 408.0500 ;
      RECT 0.6200 405.6500 453.0000 405.9500 ;
      RECT 0.0000 395.1500 453.0000 405.6500 ;
      RECT 0.6200 394.8500 453.0000 395.1500 ;
      RECT 0.0000 387.9500 453.0000 394.8500 ;
      RECT 0.6200 387.6500 452.3800 387.9500 ;
      RECT 0.0000 384.3500 453.0000 387.6500 ;
      RECT 0.0000 384.0500 452.3800 384.3500 ;
      RECT 0.0000 380.7500 453.0000 384.0500 ;
      RECT 0.6200 380.4500 452.3800 380.7500 ;
      RECT 0.0000 372.3500 453.0000 380.4500 ;
      RECT 0.6200 372.0500 453.0000 372.3500 ;
      RECT 0.0000 365.1500 453.0000 372.0500 ;
      RECT 0.0000 364.8500 452.3800 365.1500 ;
      RECT 0.0000 359.1500 453.0000 364.8500 ;
      RECT 0.0000 358.8500 452.3800 359.1500 ;
      RECT 0.0000 357.9500 453.0000 358.8500 ;
      RECT 0.6200 357.6500 453.0000 357.9500 ;
      RECT 0.0000 354.3500 453.0000 357.6500 ;
      RECT 0.6200 354.0500 452.3800 354.3500 ;
      RECT 0.0000 344.7500 453.0000 354.0500 ;
      RECT 0.6200 344.4500 453.0000 344.7500 ;
      RECT 0.0000 343.5500 453.0000 344.4500 ;
      RECT 0.6200 343.2500 453.0000 343.5500 ;
      RECT 0.0000 341.1500 453.0000 343.2500 ;
      RECT 0.6200 340.8500 453.0000 341.1500 ;
      RECT 0.0000 339.9500 453.0000 340.8500 ;
      RECT 0.0000 339.6500 452.3800 339.9500 ;
      RECT 0.0000 337.5500 453.0000 339.6500 ;
      RECT 0.6200 337.2500 452.3800 337.5500 ;
      RECT 0.0000 336.3500 453.0000 337.2500 ;
      RECT 0.6200 336.0500 452.3800 336.3500 ;
      RECT 0.0000 333.9500 453.0000 336.0500 ;
      RECT 0.6200 333.6500 453.0000 333.9500 ;
      RECT 0.0000 329.1500 453.0000 333.6500 ;
      RECT 0.6200 328.8500 452.3800 329.1500 ;
      RECT 0.0000 327.1500 453.0000 328.8500 ;
      RECT 0.6200 326.8500 453.0000 327.1500 ;
      RECT 0.0000 326.1500 453.0000 326.8500 ;
      RECT 0.6200 325.8500 453.0000 326.1500 ;
      RECT 0.0000 319.5500 453.0000 325.8500 ;
      RECT 0.6200 319.2500 453.0000 319.5500 ;
      RECT 0.0000 316.3500 453.0000 319.2500 ;
      RECT 0.6200 316.0500 453.0000 316.3500 ;
      RECT 0.0000 315.9500 453.0000 316.0500 ;
      RECT 0.6200 315.6500 453.0000 315.9500 ;
      RECT 0.0000 315.1500 453.0000 315.6500 ;
      RECT 0.6200 314.8500 453.0000 315.1500 ;
      RECT 0.0000 314.3500 453.0000 314.8500 ;
      RECT 0.6200 314.0500 453.0000 314.3500 ;
      RECT 0.0000 312.1500 453.0000 314.0500 ;
      RECT 0.6200 311.8500 453.0000 312.1500 ;
      RECT 0.0000 305.1500 453.0000 311.8500 ;
      RECT 0.6200 304.8500 452.3800 305.1500 ;
      RECT 0.0000 303.9500 453.0000 304.8500 ;
      RECT 0.0000 303.6500 452.3800 303.9500 ;
      RECT 0.0000 301.5500 453.0000 303.6500 ;
      RECT 0.6200 301.2500 452.3800 301.5500 ;
      RECT 0.0000 300.3500 453.0000 301.2500 ;
      RECT 0.6200 300.0500 453.0000 300.3500 ;
      RECT 0.0000 294.3500 453.0000 300.0500 ;
      RECT 0.0000 294.0500 452.3800 294.3500 ;
      RECT 0.0000 291.5500 453.0000 294.0500 ;
      RECT 0.6200 291.2500 453.0000 291.5500 ;
      RECT 0.0000 290.7500 453.0000 291.2500 ;
      RECT 0.6200 290.4500 453.0000 290.7500 ;
      RECT 0.0000 289.5500 453.0000 290.4500 ;
      RECT 0.0000 289.2500 452.3800 289.5500 ;
      RECT 0.0000 287.5500 453.0000 289.2500 ;
      RECT 0.6200 287.2500 453.0000 287.5500 ;
      RECT 0.0000 287.1500 453.0000 287.2500 ;
      RECT 0.0000 286.8500 452.3800 287.1500 ;
      RECT 0.0000 283.5500 453.0000 286.8500 ;
      RECT 0.0000 283.3500 452.3800 283.5500 ;
      RECT 0.6200 283.2500 452.3800 283.3500 ;
      RECT 0.6200 283.0500 453.0000 283.2500 ;
      RECT 0.0000 282.3500 453.0000 283.0500 ;
      RECT 0.6200 282.0500 452.3800 282.3500 ;
      RECT 0.0000 279.9500 453.0000 282.0500 ;
      RECT 0.6200 279.6500 452.3800 279.9500 ;
      RECT 0.0000 278.7500 453.0000 279.6500 ;
      RECT 0.0000 278.4500 452.3800 278.7500 ;
      RECT 0.0000 267.9500 453.0000 278.4500 ;
      RECT 0.6200 267.6500 453.0000 267.9500 ;
      RECT 0.0000 265.9500 453.0000 267.6500 ;
      RECT 0.6200 265.6500 453.0000 265.9500 ;
      RECT 0.0000 265.5500 453.0000 265.6500 ;
      RECT 0.0000 265.2500 452.3800 265.5500 ;
      RECT 0.0000 264.3500 453.0000 265.2500 ;
      RECT 0.0000 264.0500 452.3800 264.3500 ;
      RECT 0.0000 263.5500 453.0000 264.0500 ;
      RECT 0.6200 263.2500 453.0000 263.5500 ;
      RECT 0.0000 260.7500 453.0000 263.2500 ;
      RECT 0.0000 260.4500 452.3800 260.7500 ;
      RECT 0.0000 258.1500 453.0000 260.4500 ;
      RECT 0.6200 257.8500 453.0000 258.1500 ;
      RECT 0.0000 255.7500 453.0000 257.8500 ;
      RECT 0.6200 255.4500 453.0000 255.7500 ;
      RECT 0.0000 253.5500 453.0000 255.4500 ;
      RECT 0.0000 253.2500 452.3800 253.5500 ;
      RECT 0.0000 251.5500 453.0000 253.2500 ;
      RECT 0.6200 251.2500 453.0000 251.5500 ;
      RECT 0.0000 251.1500 453.0000 251.2500 ;
      RECT 0.0000 250.8500 452.3800 251.1500 ;
      RECT 0.0000 250.1500 453.0000 250.8500 ;
      RECT 0.6200 249.9500 453.0000 250.1500 ;
      RECT 0.6200 249.8500 452.3800 249.9500 ;
      RECT 0.0000 249.6500 452.3800 249.8500 ;
      RECT 0.0000 248.1500 453.0000 249.6500 ;
      RECT 0.6200 247.8500 453.0000 248.1500 ;
      RECT 0.0000 244.5500 453.0000 247.8500 ;
      RECT 0.6200 244.2500 453.0000 244.5500 ;
      RECT 0.0000 242.3500 453.0000 244.2500 ;
      RECT 0.6200 242.0500 453.0000 242.3500 ;
      RECT 0.0000 239.1500 453.0000 242.0500 ;
      RECT 0.0000 238.8500 452.3800 239.1500 ;
      RECT 0.0000 235.5500 453.0000 238.8500 ;
      RECT 0.0000 235.2500 452.3800 235.5500 ;
      RECT 0.0000 231.9500 453.0000 235.2500 ;
      RECT 0.0000 231.6500 452.3800 231.9500 ;
      RECT 0.0000 229.5500 453.0000 231.6500 ;
      RECT 0.0000 229.2500 452.3800 229.5500 ;
      RECT 0.0000 226.3500 453.0000 229.2500 ;
      RECT 0.0000 226.0500 452.3800 226.3500 ;
      RECT 0.0000 225.9500 453.0000 226.0500 ;
      RECT 0.0000 225.6500 452.3800 225.9500 ;
      RECT 0.0000 225.5500 453.0000 225.6500 ;
      RECT 0.0000 225.2500 452.3800 225.5500 ;
      RECT 0.0000 224.3500 453.0000 225.2500 ;
      RECT 0.6200 224.0500 453.0000 224.3500 ;
      RECT 0.0000 214.5500 453.0000 224.0500 ;
      RECT 0.6200 214.2500 453.0000 214.5500 ;
      RECT 0.0000 209.7500 453.0000 214.2500 ;
      RECT 0.6200 209.4500 453.0000 209.7500 ;
      RECT 0.0000 208.7500 453.0000 209.4500 ;
      RECT 0.6200 208.4500 453.0000 208.7500 ;
      RECT 0.0000 202.3500 453.0000 208.4500 ;
      RECT 0.6200 202.0500 453.0000 202.3500 ;
      RECT 0.0000 195.7500 453.0000 202.0500 ;
      RECT 0.6200 195.4500 453.0000 195.7500 ;
      RECT 0.0000 194.5500 453.0000 195.4500 ;
      RECT 0.6200 194.2500 453.0000 194.5500 ;
      RECT 0.0000 187.1500 453.0000 194.2500 ;
      RECT 0.6200 186.8500 453.0000 187.1500 ;
      RECT 0.0000 179.5500 453.0000 186.8500 ;
      RECT 0.6200 179.2500 453.0000 179.5500 ;
      RECT 0.0000 178.7500 453.0000 179.2500 ;
      RECT 0.6200 178.4500 453.0000 178.7500 ;
      RECT 0.0000 177.3500 453.0000 178.4500 ;
      RECT 0.6200 177.0500 453.0000 177.3500 ;
      RECT 0.0000 174.9500 453.0000 177.0500 ;
      RECT 0.6200 174.6500 453.0000 174.9500 ;
      RECT 0.0000 172.1500 453.0000 174.6500 ;
      RECT 0.6200 171.8500 453.0000 172.1500 ;
      RECT 0.0000 159.9500 453.0000 171.8500 ;
      RECT 0.6200 159.6500 453.0000 159.9500 ;
      RECT 0.0000 157.7500 453.0000 159.6500 ;
      RECT 0.6200 157.4500 453.0000 157.7500 ;
      RECT 0.0000 156.5500 453.0000 157.4500 ;
      RECT 0.6200 156.2500 453.0000 156.5500 ;
      RECT 0.0000 154.3500 453.0000 156.2500 ;
      RECT 0.6200 154.0500 453.0000 154.3500 ;
      RECT 0.0000 146.5500 453.0000 154.0500 ;
      RECT 0.6200 146.2500 453.0000 146.5500 ;
      RECT 0.0000 141.5500 453.0000 146.2500 ;
      RECT 0.6200 141.2500 453.0000 141.5500 ;
      RECT 0.0000 137.7500 453.0000 141.2500 ;
      RECT 0.6200 137.4500 453.0000 137.7500 ;
      RECT 0.0000 135.9500 453.0000 137.4500 ;
      RECT 0.6200 135.6500 453.0000 135.9500 ;
      RECT 0.0000 128.7500 453.0000 135.6500 ;
      RECT 0.6200 128.4500 453.0000 128.7500 ;
      RECT 0.0000 121.3500 453.0000 128.4500 ;
      RECT 0.6200 121.0500 453.0000 121.3500 ;
      RECT 0.0000 119.3500 453.0000 121.0500 ;
      RECT 0.6200 119.0500 453.0000 119.3500 ;
      RECT 0.0000 118.5500 453.0000 119.0500 ;
      RECT 0.6200 118.2500 453.0000 118.5500 ;
      RECT 0.0000 113.3500 453.0000 118.2500 ;
      RECT 0.6200 113.0500 453.0000 113.3500 ;
      RECT 0.0000 111.3500 453.0000 113.0500 ;
      RECT 0.6200 111.0500 453.0000 111.3500 ;
      RECT 0.0000 76.1500 453.0000 111.0500 ;
      RECT 0.6200 75.8500 453.0000 76.1500 ;
      RECT 0.0000 74.7500 453.0000 75.8500 ;
      RECT 0.6200 74.4500 453.0000 74.7500 ;
      RECT 0.0000 67.5500 453.0000 74.4500 ;
      RECT 0.6200 67.2500 453.0000 67.5500 ;
      RECT 0.0000 0.0000 453.0000 67.2500 ;
    LAYER M4 ;
      RECT 226.6500 451.5800 453.0000 452.2000 ;
      RECT 94.8500 451.5800 226.3500 452.2000 ;
      RECT 0.0000 451.5800 94.5500 452.2000 ;
      RECT 0.0000 0.6200 453.0000 451.5800 ;
      RECT 327.4500 0.0000 453.0000 0.6200 ;
      RECT 306.2500 0.0000 327.1500 0.6200 ;
      RECT 299.6500 0.0000 305.9500 0.6200 ;
      RECT 282.0500 0.0000 299.3500 0.6200 ;
      RECT 262.6500 0.0000 281.7500 0.6200 ;
      RECT 262.2500 0.0000 262.3500 0.6200 ;
      RECT 256.6500 0.0000 261.9500 0.6200 ;
      RECT 237.0500 0.0000 256.3500 0.6200 ;
      RECT 226.6500 0.0000 236.7500 0.6200 ;
      RECT 224.0500 0.0000 226.3500 0.6200 ;
      RECT 216.0500 0.0000 223.7500 0.6200 ;
      RECT 211.0500 0.0000 215.7500 0.6200 ;
      RECT 191.0500 0.0000 210.7500 0.6200 ;
      RECT 69.0500 0.0000 190.7500 0.6200 ;
      RECT 0.0000 0.0000 68.7500 0.6200 ;
    LAYER M5 ;
      RECT 0.0000 405.9500 453.0000 452.2000 ;
      RECT 0.6200 405.6500 453.0000 405.9500 ;
      RECT 0.0000 380.7500 453.0000 405.6500 ;
      RECT 0.0000 380.4500 452.3800 380.7500 ;
      RECT 0.0000 341.1500 453.0000 380.4500 ;
      RECT 0.6200 340.8500 453.0000 341.1500 ;
      RECT 0.0000 337.5500 453.0000 340.8500 ;
      RECT 0.0000 337.2500 452.3800 337.5500 ;
      RECT 0.0000 336.3500 453.0000 337.2500 ;
      RECT 0.6200 336.0500 453.0000 336.3500 ;
      RECT 0.0000 329.1500 453.0000 336.0500 ;
      RECT 0.6200 328.8500 452.3800 329.1500 ;
      RECT 0.0000 327.1500 453.0000 328.8500 ;
      RECT 0.6200 326.8500 453.0000 327.1500 ;
      RECT 0.0000 312.3500 453.0000 326.8500 ;
      RECT 0.6200 312.0500 453.0000 312.3500 ;
      RECT 0.0000 301.5500 453.0000 312.0500 ;
      RECT 0.6200 301.2500 452.3800 301.5500 ;
      RECT 0.0000 289.5500 453.0000 301.2500 ;
      RECT 0.0000 289.2500 452.3800 289.5500 ;
      RECT 0.0000 287.1500 453.0000 289.2500 ;
      RECT 0.0000 286.8500 452.3800 287.1500 ;
      RECT 0.0000 282.3500 453.0000 286.8500 ;
      RECT 0.0000 282.0500 452.3800 282.3500 ;
      RECT 0.0000 279.9500 453.0000 282.0500 ;
      RECT 0.0000 279.6500 452.3800 279.9500 ;
      RECT 0.0000 239.1500 453.0000 279.6500 ;
      RECT 0.0000 238.8500 452.3800 239.1500 ;
      RECT 0.0000 229.5500 453.0000 238.8500 ;
      RECT 0.0000 229.2500 452.3800 229.5500 ;
      RECT 0.0000 225.9500 453.0000 229.2500 ;
      RECT 0.0000 225.6500 452.3800 225.9500 ;
      RECT 0.0000 202.1500 453.0000 225.6500 ;
      RECT 0.6200 201.8500 453.0000 202.1500 ;
      RECT 0.0000 0.0000 453.0000 201.8500 ;
    LAYER M6 ;
      RECT 226.6500 451.5800 453.0000 452.2000 ;
      RECT 0.0000 451.5800 226.3500 452.2000 ;
      RECT 0.0000 0.6200 453.0000 451.5800 ;
      RECT 299.6500 0.0000 453.0000 0.6200 ;
      RECT 237.0500 0.0000 299.3500 0.6200 ;
      RECT 226.6500 0.0000 236.7500 0.6200 ;
      RECT 0.0000 0.0000 226.3500 0.6200 ;
    LAYER M7 ;
      RECT 0.0000 381.4000 453.0000 452.2000 ;
      RECT 0.0000 380.2000 451.1850 381.4000 ;
      RECT 0.0000 329.4000 453.0000 380.2000 ;
      RECT 0.0000 328.2000 451.1850 329.4000 ;
      RECT 0.0000 327.8000 453.0000 328.2000 ;
      RECT 1.8150 326.6000 453.0000 327.8000 ;
      RECT 0.0000 239.8000 453.0000 326.6000 ;
      RECT 0.0000 238.6000 451.1850 239.8000 ;
      RECT 0.0000 226.2000 453.0000 238.6000 ;
      RECT 0.0000 225.0000 451.1850 226.2000 ;
      RECT 0.0000 0.0000 453.0000 225.0000 ;
    LAYER M8 ;
      RECT 227.1000 450.3850 453.0000 452.2000 ;
      RECT 0.0000 450.3850 225.9000 452.2000 ;
      RECT 0.0000 1.8150 453.0000 450.3850 ;
      RECT 227.1000 0.0000 453.0000 1.8150 ;
      RECT 0.0000 0.0000 225.9000 1.8150 ;
  END
END core

END LIBRARY
